VERSION 5.8 ;
BUSBITCHARS "[]" ;
DIVIDERCHAR "/" ;
UNITS
    DATABASE MICRONS 2000 ;
END UNITS

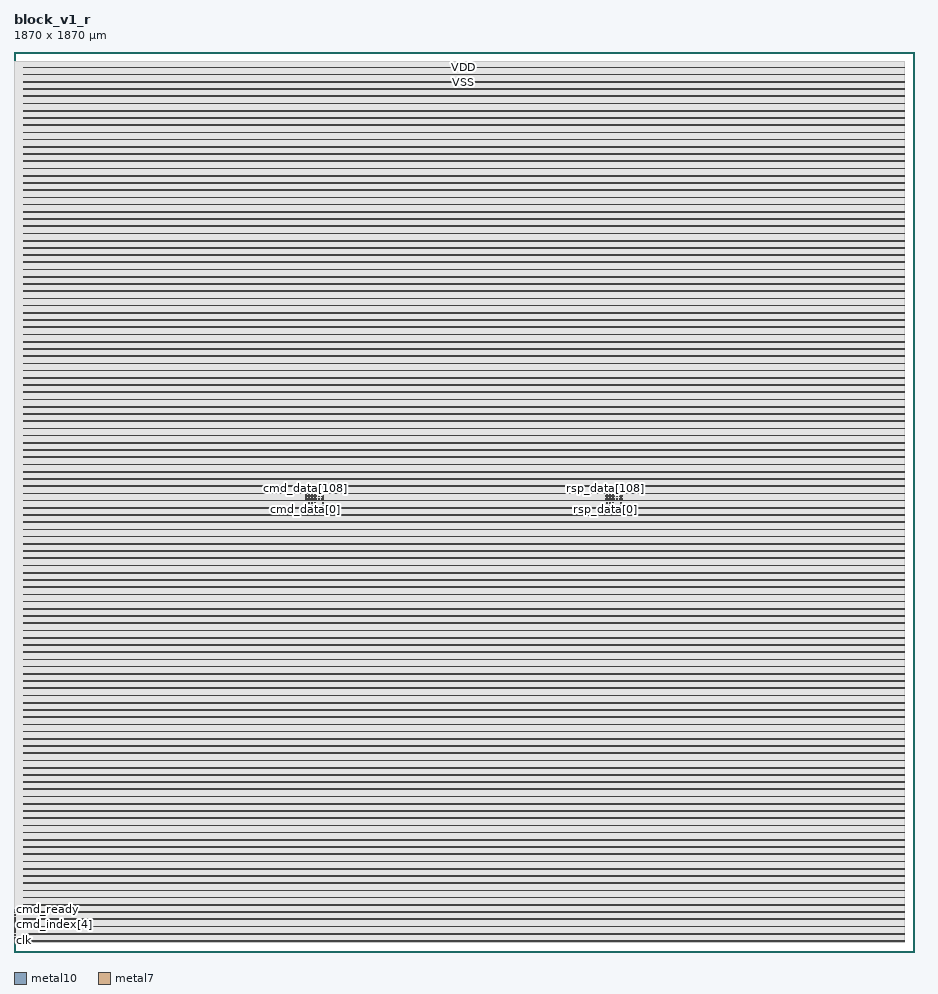
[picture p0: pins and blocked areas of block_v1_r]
MACRO block_v1_r
  FOREIGN block_v1_r 0 0 ;
  CLASS BLOCK ;
  SIZE 1870 BY 1870 ;
  PIN busy
    DIRECTION OUTPUT ;
    USE SIGNAL ;
    PORT
      LAYER metal10 ;
        RECT  1.295 20.47 2.095 21.27 ;
    END
  END busy
  PIN clk
    DIRECTION INPUT ;
    USE SIGNAL ;
    PORT
      LAYER metal10 ;
        RECT  1.295 23.67 2.095 24.47 ;
    END
  END clk
  PIN cmd_data[0]
    DIRECTION INPUT ;
    USE SIGNAL ;
    PORT
      LAYER metal10 ;
        RECT  606.095 918.07 606.895 918.87 ;
    END
  END cmd_data[0]
  PIN cmd_data[100]
    DIRECTION INPUT ;
    USE SIGNAL ;
    PORT
      LAYER metal10 ;
        RECT  618.895 943.67 619.695 944.47 ;
    END
  END cmd_data[100]
  PIN cmd_data[101]
    DIRECTION INPUT ;
    USE SIGNAL ;
    PORT
      LAYER metal10 ;
        RECT  622.095 943.67 622.895 944.47 ;
    END
  END cmd_data[101]
  PIN cmd_data[102]
    DIRECTION INPUT ;
    USE SIGNAL ;
    PORT
      LAYER metal10 ;
        RECT  625.295 943.67 626.095 944.47 ;
    END
  END cmd_data[102]
  PIN cmd_data[103]
    DIRECTION INPUT ;
    USE SIGNAL ;
    PORT
      LAYER metal10 ;
        RECT  628.495 943.67 629.295 944.47 ;
    END
  END cmd_data[103]
  PIN cmd_data[104]
    DIRECTION INPUT ;
    USE SIGNAL ;
    PORT
      LAYER metal10 ;
        RECT  631.695 943.67 632.495 944.47 ;
    END
  END cmd_data[104]
  PIN cmd_data[105]
    DIRECTION INPUT ;
    USE SIGNAL ;
    PORT
      LAYER metal10 ;
        RECT  634.895 943.67 635.695 944.47 ;
    END
  END cmd_data[105]
  PIN cmd_data[106]
    DIRECTION INPUT ;
    USE SIGNAL ;
    PORT
      LAYER metal10 ;
        RECT  638.095 943.67 638.895 944.47 ;
    END
  END cmd_data[106]
  PIN cmd_data[107]
    DIRECTION INPUT ;
    USE SIGNAL ;
    PORT
      LAYER metal10 ;
        RECT  641.295 943.67 642.095 944.47 ;
    END
  END cmd_data[107]
  PIN cmd_data[108]
    DIRECTION INPUT ;
    USE SIGNAL ;
    PORT
      LAYER metal10 ;
        RECT  606.095 946.87 606.895 947.67 ;
    END
  END cmd_data[108]
  PIN cmd_data[109]
    DIRECTION INPUT ;
    USE SIGNAL ;
    PORT
      LAYER metal10 ;
        RECT  609.295 946.87 610.095 947.67 ;
    END
  END cmd_data[109]
  PIN cmd_data[10]
    DIRECTION INPUT ;
    USE SIGNAL ;
    PORT
      LAYER metal10 ;
        RECT  638.095 918.07 638.895 918.87 ;
    END
  END cmd_data[10]
  PIN cmd_data[110]
    DIRECTION INPUT ;
    USE SIGNAL ;
    PORT
      LAYER metal10 ;
        RECT  612.495 946.87 613.295 947.67 ;
    END
  END cmd_data[110]
  PIN cmd_data[111]
    DIRECTION INPUT ;
    USE SIGNAL ;
    PORT
      LAYER metal10 ;
        RECT  615.695 946.87 616.495 947.67 ;
    END
  END cmd_data[111]
  PIN cmd_data[112]
    DIRECTION INPUT ;
    USE SIGNAL ;
    PORT
      LAYER metal10 ;
        RECT  618.895 946.87 619.695 947.67 ;
    END
  END cmd_data[112]
  PIN cmd_data[113]
    DIRECTION INPUT ;
    USE SIGNAL ;
    PORT
      LAYER metal10 ;
        RECT  622.095 946.87 622.895 947.67 ;
    END
  END cmd_data[113]
  PIN cmd_data[114]
    DIRECTION INPUT ;
    USE SIGNAL ;
    PORT
      LAYER metal10 ;
        RECT  625.295 946.87 626.095 947.67 ;
    END
  END cmd_data[114]
  PIN cmd_data[115]
    DIRECTION INPUT ;
    USE SIGNAL ;
    PORT
      LAYER metal10 ;
        RECT  628.495 946.87 629.295 947.67 ;
    END
  END cmd_data[115]
  PIN cmd_data[116]
    DIRECTION INPUT ;
    USE SIGNAL ;
    PORT
      LAYER metal10 ;
        RECT  631.695 946.87 632.495 947.67 ;
    END
  END cmd_data[116]
  PIN cmd_data[117]
    DIRECTION INPUT ;
    USE SIGNAL ;
    PORT
      LAYER metal10 ;
        RECT  634.895 946.87 635.695 947.67 ;
    END
  END cmd_data[117]
  PIN cmd_data[118]
    DIRECTION INPUT ;
    USE SIGNAL ;
    PORT
      LAYER metal10 ;
        RECT  638.095 946.87 638.895 947.67 ;
    END
  END cmd_data[118]
  PIN cmd_data[119]
    DIRECTION INPUT ;
    USE SIGNAL ;
    PORT
      LAYER metal10 ;
        RECT  641.295 946.87 642.095 947.67 ;
    END
  END cmd_data[119]
  PIN cmd_data[11]
    DIRECTION INPUT ;
    USE SIGNAL ;
    PORT
      LAYER metal10 ;
        RECT  641.295 918.07 642.095 918.87 ;
    END
  END cmd_data[11]
  PIN cmd_data[120]
    DIRECTION INPUT ;
    USE SIGNAL ;
    PORT
      LAYER metal10 ;
        RECT  606.095 950.07 606.895 950.87 ;
    END
  END cmd_data[120]
  PIN cmd_data[121]
    DIRECTION INPUT ;
    USE SIGNAL ;
    PORT
      LAYER metal10 ;
        RECT  609.295 950.07 610.095 950.87 ;
    END
  END cmd_data[121]
  PIN cmd_data[122]
    DIRECTION INPUT ;
    USE SIGNAL ;
    PORT
      LAYER metal10 ;
        RECT  612.495 950.07 613.295 950.87 ;
    END
  END cmd_data[122]
  PIN cmd_data[123]
    DIRECTION INPUT ;
    USE SIGNAL ;
    PORT
      LAYER metal10 ;
        RECT  615.695 950.07 616.495 950.87 ;
    END
  END cmd_data[123]
  PIN cmd_data[124]
    DIRECTION INPUT ;
    USE SIGNAL ;
    PORT
      LAYER metal10 ;
        RECT  618.895 950.07 619.695 950.87 ;
    END
  END cmd_data[124]
  PIN cmd_data[125]
    DIRECTION INPUT ;
    USE SIGNAL ;
    PORT
      LAYER metal10 ;
        RECT  622.095 950.07 622.895 950.87 ;
    END
  END cmd_data[125]
  PIN cmd_data[126]
    DIRECTION INPUT ;
    USE SIGNAL ;
    PORT
      LAYER metal10 ;
        RECT  625.295 950.07 626.095 950.87 ;
    END
  END cmd_data[126]
  PIN cmd_data[127]
    DIRECTION INPUT ;
    USE SIGNAL ;
    PORT
      LAYER metal10 ;
        RECT  628.495 950.07 629.295 950.87 ;
    END
  END cmd_data[127]
  PIN cmd_data[12]
    DIRECTION INPUT ;
    USE SIGNAL ;
    PORT
      LAYER metal10 ;
        RECT  606.095 921.27 606.895 922.07 ;
    END
  END cmd_data[12]
  PIN cmd_data[13]
    DIRECTION INPUT ;
    USE SIGNAL ;
    PORT
      LAYER metal10 ;
        RECT  609.295 921.27 610.095 922.07 ;
    END
  END cmd_data[13]
  PIN cmd_data[14]
    DIRECTION INPUT ;
    USE SIGNAL ;
    PORT
      LAYER metal10 ;
        RECT  612.495 921.27 613.295 922.07 ;
    END
  END cmd_data[14]
  PIN cmd_data[15]
    DIRECTION INPUT ;
    USE SIGNAL ;
    PORT
      LAYER metal10 ;
        RECT  615.695 921.27 616.495 922.07 ;
    END
  END cmd_data[15]
  PIN cmd_data[16]
    DIRECTION INPUT ;
    USE SIGNAL ;
    PORT
      LAYER metal10 ;
        RECT  618.895 921.27 619.695 922.07 ;
    END
  END cmd_data[16]
  PIN cmd_data[17]
    DIRECTION INPUT ;
    USE SIGNAL ;
    PORT
      LAYER metal10 ;
        RECT  622.095 921.27 622.895 922.07 ;
    END
  END cmd_data[17]
  PIN cmd_data[18]
    DIRECTION INPUT ;
    USE SIGNAL ;
    PORT
      LAYER metal10 ;
        RECT  625.295 921.27 626.095 922.07 ;
    END
  END cmd_data[18]
  PIN cmd_data[19]
    DIRECTION INPUT ;
    USE SIGNAL ;
    PORT
      LAYER metal10 ;
        RECT  628.495 921.27 629.295 922.07 ;
    END
  END cmd_data[19]
  PIN cmd_data[1]
    DIRECTION INPUT ;
    USE SIGNAL ;
    PORT
      LAYER metal10 ;
        RECT  609.295 918.07 610.095 918.87 ;
    END
  END cmd_data[1]
  PIN cmd_data[20]
    DIRECTION INPUT ;
    USE SIGNAL ;
    PORT
      LAYER metal10 ;
        RECT  631.695 921.27 632.495 922.07 ;
    END
  END cmd_data[20]
  PIN cmd_data[21]
    DIRECTION INPUT ;
    USE SIGNAL ;
    PORT
      LAYER metal10 ;
        RECT  634.895 921.27 635.695 922.07 ;
    END
  END cmd_data[21]
  PIN cmd_data[22]
    DIRECTION INPUT ;
    USE SIGNAL ;
    PORT
      LAYER metal10 ;
        RECT  638.095 921.27 638.895 922.07 ;
    END
  END cmd_data[22]
  PIN cmd_data[23]
    DIRECTION INPUT ;
    USE SIGNAL ;
    PORT
      LAYER metal10 ;
        RECT  641.295 921.27 642.095 922.07 ;
    END
  END cmd_data[23]
  PIN cmd_data[24]
    DIRECTION INPUT ;
    USE SIGNAL ;
    PORT
      LAYER metal10 ;
        RECT  606.095 924.47 606.895 925.27 ;
    END
  END cmd_data[24]
  PIN cmd_data[25]
    DIRECTION INPUT ;
    USE SIGNAL ;
    PORT
      LAYER metal10 ;
        RECT  609.295 924.47 610.095 925.27 ;
    END
  END cmd_data[25]
  PIN cmd_data[26]
    DIRECTION INPUT ;
    USE SIGNAL ;
    PORT
      LAYER metal10 ;
        RECT  612.495 924.47 613.295 925.27 ;
    END
  END cmd_data[26]
  PIN cmd_data[27]
    DIRECTION INPUT ;
    USE SIGNAL ;
    PORT
      LAYER metal10 ;
        RECT  615.695 924.47 616.495 925.27 ;
    END
  END cmd_data[27]
  PIN cmd_data[28]
    DIRECTION INPUT ;
    USE SIGNAL ;
    PORT
      LAYER metal10 ;
        RECT  618.895 924.47 619.695 925.27 ;
    END
  END cmd_data[28]
  PIN cmd_data[29]
    DIRECTION INPUT ;
    USE SIGNAL ;
    PORT
      LAYER metal10 ;
        RECT  622.095 924.47 622.895 925.27 ;
    END
  END cmd_data[29]
  PIN cmd_data[2]
    DIRECTION INPUT ;
    USE SIGNAL ;
    PORT
      LAYER metal10 ;
        RECT  612.495 918.07 613.295 918.87 ;
    END
  END cmd_data[2]
  PIN cmd_data[30]
    DIRECTION INPUT ;
    USE SIGNAL ;
    PORT
      LAYER metal10 ;
        RECT  625.295 924.47 626.095 925.27 ;
    END
  END cmd_data[30]
  PIN cmd_data[31]
    DIRECTION INPUT ;
    USE SIGNAL ;
    PORT
      LAYER metal10 ;
        RECT  628.495 924.47 629.295 925.27 ;
    END
  END cmd_data[31]
  PIN cmd_data[32]
    DIRECTION INPUT ;
    USE SIGNAL ;
    PORT
      LAYER metal10 ;
        RECT  631.695 924.47 632.495 925.27 ;
    END
  END cmd_data[32]
  PIN cmd_data[33]
    DIRECTION INPUT ;
    USE SIGNAL ;
    PORT
      LAYER metal10 ;
        RECT  634.895 924.47 635.695 925.27 ;
    END
  END cmd_data[33]
  PIN cmd_data[34]
    DIRECTION INPUT ;
    USE SIGNAL ;
    PORT
      LAYER metal10 ;
        RECT  638.095 924.47 638.895 925.27 ;
    END
  END cmd_data[34]
  PIN cmd_data[35]
    DIRECTION INPUT ;
    USE SIGNAL ;
    PORT
      LAYER metal10 ;
        RECT  641.295 924.47 642.095 925.27 ;
    END
  END cmd_data[35]
  PIN cmd_data[36]
    DIRECTION INPUT ;
    USE SIGNAL ;
    PORT
      LAYER metal10 ;
        RECT  606.095 927.67 606.895 928.47 ;
    END
  END cmd_data[36]
  PIN cmd_data[37]
    DIRECTION INPUT ;
    USE SIGNAL ;
    PORT
      LAYER metal10 ;
        RECT  609.295 927.67 610.095 928.47 ;
    END
  END cmd_data[37]
  PIN cmd_data[38]
    DIRECTION INPUT ;
    USE SIGNAL ;
    PORT
      LAYER metal10 ;
        RECT  612.495 927.67 613.295 928.47 ;
    END
  END cmd_data[38]
  PIN cmd_data[39]
    DIRECTION INPUT ;
    USE SIGNAL ;
    PORT
      LAYER metal10 ;
        RECT  615.695 927.67 616.495 928.47 ;
    END
  END cmd_data[39]
  PIN cmd_data[3]
    DIRECTION INPUT ;
    USE SIGNAL ;
    PORT
      LAYER metal10 ;
        RECT  615.695 918.07 616.495 918.87 ;
    END
  END cmd_data[3]
  PIN cmd_data[40]
    DIRECTION INPUT ;
    USE SIGNAL ;
    PORT
      LAYER metal10 ;
        RECT  618.895 927.67 619.695 928.47 ;
    END
  END cmd_data[40]
  PIN cmd_data[41]
    DIRECTION INPUT ;
    USE SIGNAL ;
    PORT
      LAYER metal10 ;
        RECT  622.095 927.67 622.895 928.47 ;
    END
  END cmd_data[41]
  PIN cmd_data[42]
    DIRECTION INPUT ;
    USE SIGNAL ;
    PORT
      LAYER metal10 ;
        RECT  625.295 927.67 626.095 928.47 ;
    END
  END cmd_data[42]
  PIN cmd_data[43]
    DIRECTION INPUT ;
    USE SIGNAL ;
    PORT
      LAYER metal10 ;
        RECT  628.495 927.67 629.295 928.47 ;
    END
  END cmd_data[43]
  PIN cmd_data[44]
    DIRECTION INPUT ;
    USE SIGNAL ;
    PORT
      LAYER metal10 ;
        RECT  631.695 927.67 632.495 928.47 ;
    END
  END cmd_data[44]
  PIN cmd_data[45]
    DIRECTION INPUT ;
    USE SIGNAL ;
    PORT
      LAYER metal10 ;
        RECT  634.895 927.67 635.695 928.47 ;
    END
  END cmd_data[45]
  PIN cmd_data[46]
    DIRECTION INPUT ;
    USE SIGNAL ;
    PORT
      LAYER metal10 ;
        RECT  638.095 927.67 638.895 928.47 ;
    END
  END cmd_data[46]
  PIN cmd_data[47]
    DIRECTION INPUT ;
    USE SIGNAL ;
    PORT
      LAYER metal10 ;
        RECT  641.295 927.67 642.095 928.47 ;
    END
  END cmd_data[47]
  PIN cmd_data[48]
    DIRECTION INPUT ;
    USE SIGNAL ;
    PORT
      LAYER metal10 ;
        RECT  606.095 930.87 606.895 931.67 ;
    END
  END cmd_data[48]
  PIN cmd_data[49]
    DIRECTION INPUT ;
    USE SIGNAL ;
    PORT
      LAYER metal10 ;
        RECT  609.295 930.87 610.095 931.67 ;
    END
  END cmd_data[49]
  PIN cmd_data[4]
    DIRECTION INPUT ;
    USE SIGNAL ;
    PORT
      LAYER metal10 ;
        RECT  618.895 918.07 619.695 918.87 ;
    END
  END cmd_data[4]
  PIN cmd_data[50]
    DIRECTION INPUT ;
    USE SIGNAL ;
    PORT
      LAYER metal10 ;
        RECT  612.495 930.87 613.295 931.67 ;
    END
  END cmd_data[50]
  PIN cmd_data[51]
    DIRECTION INPUT ;
    USE SIGNAL ;
    PORT
      LAYER metal10 ;
        RECT  615.695 930.87 616.495 931.67 ;
    END
  END cmd_data[51]
  PIN cmd_data[52]
    DIRECTION INPUT ;
    USE SIGNAL ;
    PORT
      LAYER metal10 ;
        RECT  618.895 930.87 619.695 931.67 ;
    END
  END cmd_data[52]
  PIN cmd_data[53]
    DIRECTION INPUT ;
    USE SIGNAL ;
    PORT
      LAYER metal10 ;
        RECT  622.095 930.87 622.895 931.67 ;
    END
  END cmd_data[53]
  PIN cmd_data[54]
    DIRECTION INPUT ;
    USE SIGNAL ;
    PORT
      LAYER metal10 ;
        RECT  625.295 930.87 626.095 931.67 ;
    END
  END cmd_data[54]
  PIN cmd_data[55]
    DIRECTION INPUT ;
    USE SIGNAL ;
    PORT
      LAYER metal10 ;
        RECT  628.495 930.87 629.295 931.67 ;
    END
  END cmd_data[55]
  PIN cmd_data[56]
    DIRECTION INPUT ;
    USE SIGNAL ;
    PORT
      LAYER metal10 ;
        RECT  631.695 930.87 632.495 931.67 ;
    END
  END cmd_data[56]
  PIN cmd_data[57]
    DIRECTION INPUT ;
    USE SIGNAL ;
    PORT
      LAYER metal10 ;
        RECT  634.895 930.87 635.695 931.67 ;
    END
  END cmd_data[57]
  PIN cmd_data[58]
    DIRECTION INPUT ;
    USE SIGNAL ;
    PORT
      LAYER metal10 ;
        RECT  638.095 930.87 638.895 931.67 ;
    END
  END cmd_data[58]
  PIN cmd_data[59]
    DIRECTION INPUT ;
    USE SIGNAL ;
    PORT
      LAYER metal10 ;
        RECT  641.295 930.87 642.095 931.67 ;
    END
  END cmd_data[59]
  PIN cmd_data[5]
    DIRECTION INPUT ;
    USE SIGNAL ;
    PORT
      LAYER metal10 ;
        RECT  622.095 918.07 622.895 918.87 ;
    END
  END cmd_data[5]
  PIN cmd_data[60]
    DIRECTION INPUT ;
    USE SIGNAL ;
    PORT
      LAYER metal10 ;
        RECT  606.095 934.07 606.895 934.87 ;
    END
  END cmd_data[60]
  PIN cmd_data[61]
    DIRECTION INPUT ;
    USE SIGNAL ;
    PORT
      LAYER metal10 ;
        RECT  609.295 934.07 610.095 934.87 ;
    END
  END cmd_data[61]
  PIN cmd_data[62]
    DIRECTION INPUT ;
    USE SIGNAL ;
    PORT
      LAYER metal10 ;
        RECT  612.495 934.07 613.295 934.87 ;
    END
  END cmd_data[62]
  PIN cmd_data[63]
    DIRECTION INPUT ;
    USE SIGNAL ;
    PORT
      LAYER metal10 ;
        RECT  615.695 934.07 616.495 934.87 ;
    END
  END cmd_data[63]
  PIN cmd_data[64]
    DIRECTION INPUT ;
    USE SIGNAL ;
    PORT
      LAYER metal10 ;
        RECT  618.895 934.07 619.695 934.87 ;
    END
  END cmd_data[64]
  PIN cmd_data[65]
    DIRECTION INPUT ;
    USE SIGNAL ;
    PORT
      LAYER metal10 ;
        RECT  622.095 934.07 622.895 934.87 ;
    END
  END cmd_data[65]
  PIN cmd_data[66]
    DIRECTION INPUT ;
    USE SIGNAL ;
    PORT
      LAYER metal10 ;
        RECT  625.295 934.07 626.095 934.87 ;
    END
  END cmd_data[66]
  PIN cmd_data[67]
    DIRECTION INPUT ;
    USE SIGNAL ;
    PORT
      LAYER metal10 ;
        RECT  628.495 934.07 629.295 934.87 ;
    END
  END cmd_data[67]
  PIN cmd_data[68]
    DIRECTION INPUT ;
    USE SIGNAL ;
    PORT
      LAYER metal10 ;
        RECT  631.695 934.07 632.495 934.87 ;
    END
  END cmd_data[68]
  PIN cmd_data[69]
    DIRECTION INPUT ;
    USE SIGNAL ;
    PORT
      LAYER metal10 ;
        RECT  634.895 934.07 635.695 934.87 ;
    END
  END cmd_data[69]
  PIN cmd_data[6]
    DIRECTION INPUT ;
    USE SIGNAL ;
    PORT
      LAYER metal10 ;
        RECT  625.295 918.07 626.095 918.87 ;
    END
  END cmd_data[6]
  PIN cmd_data[70]
    DIRECTION INPUT ;
    USE SIGNAL ;
    PORT
      LAYER metal10 ;
        RECT  638.095 934.07 638.895 934.87 ;
    END
  END cmd_data[70]
  PIN cmd_data[71]
    DIRECTION INPUT ;
    USE SIGNAL ;
    PORT
      LAYER metal10 ;
        RECT  641.295 934.07 642.095 934.87 ;
    END
  END cmd_data[71]
  PIN cmd_data[72]
    DIRECTION INPUT ;
    USE SIGNAL ;
    PORT
      LAYER metal10 ;
        RECT  606.095 937.27 606.895 938.07 ;
    END
  END cmd_data[72]
  PIN cmd_data[73]
    DIRECTION INPUT ;
    USE SIGNAL ;
    PORT
      LAYER metal10 ;
        RECT  609.295 937.27 610.095 938.07 ;
    END
  END cmd_data[73]
  PIN cmd_data[74]
    DIRECTION INPUT ;
    USE SIGNAL ;
    PORT
      LAYER metal10 ;
        RECT  612.495 937.27 613.295 938.07 ;
    END
  END cmd_data[74]
  PIN cmd_data[75]
    DIRECTION INPUT ;
    USE SIGNAL ;
    PORT
      LAYER metal10 ;
        RECT  615.695 937.27 616.495 938.07 ;
    END
  END cmd_data[75]
  PIN cmd_data[76]
    DIRECTION INPUT ;
    USE SIGNAL ;
    PORT
      LAYER metal10 ;
        RECT  618.895 937.27 619.695 938.07 ;
    END
  END cmd_data[76]
  PIN cmd_data[77]
    DIRECTION INPUT ;
    USE SIGNAL ;
    PORT
      LAYER metal10 ;
        RECT  622.095 937.27 622.895 938.07 ;
    END
  END cmd_data[77]
  PIN cmd_data[78]
    DIRECTION INPUT ;
    USE SIGNAL ;
    PORT
      LAYER metal10 ;
        RECT  625.295 937.27 626.095 938.07 ;
    END
  END cmd_data[78]
  PIN cmd_data[79]
    DIRECTION INPUT ;
    USE SIGNAL ;
    PORT
      LAYER metal10 ;
        RECT  628.495 937.27 629.295 938.07 ;
    END
  END cmd_data[79]
  PIN cmd_data[7]
    DIRECTION INPUT ;
    USE SIGNAL ;
    PORT
      LAYER metal10 ;
        RECT  628.495 918.07 629.295 918.87 ;
    END
  END cmd_data[7]
  PIN cmd_data[80]
    DIRECTION INPUT ;
    USE SIGNAL ;
    PORT
      LAYER metal10 ;
        RECT  631.695 937.27 632.495 938.07 ;
    END
  END cmd_data[80]
  PIN cmd_data[81]
    DIRECTION INPUT ;
    USE SIGNAL ;
    PORT
      LAYER metal10 ;
        RECT  634.895 937.27 635.695 938.07 ;
    END
  END cmd_data[81]
  PIN cmd_data[82]
    DIRECTION INPUT ;
    USE SIGNAL ;
    PORT
      LAYER metal10 ;
        RECT  638.095 937.27 638.895 938.07 ;
    END
  END cmd_data[82]
  PIN cmd_data[83]
    DIRECTION INPUT ;
    USE SIGNAL ;
    PORT
      LAYER metal10 ;
        RECT  641.295 937.27 642.095 938.07 ;
    END
  END cmd_data[83]
  PIN cmd_data[84]
    DIRECTION INPUT ;
    USE SIGNAL ;
    PORT
      LAYER metal10 ;
        RECT  606.095 940.47 606.895 941.27 ;
    END
  END cmd_data[84]
  PIN cmd_data[85]
    DIRECTION INPUT ;
    USE SIGNAL ;
    PORT
      LAYER metal10 ;
        RECT  609.295 940.47 610.095 941.27 ;
    END
  END cmd_data[85]
  PIN cmd_data[86]
    DIRECTION INPUT ;
    USE SIGNAL ;
    PORT
      LAYER metal10 ;
        RECT  612.495 940.47 613.295 941.27 ;
    END
  END cmd_data[86]
  PIN cmd_data[87]
    DIRECTION INPUT ;
    USE SIGNAL ;
    PORT
      LAYER metal10 ;
        RECT  615.695 940.47 616.495 941.27 ;
    END
  END cmd_data[87]
  PIN cmd_data[88]
    DIRECTION INPUT ;
    USE SIGNAL ;
    PORT
      LAYER metal10 ;
        RECT  618.895 940.47 619.695 941.27 ;
    END
  END cmd_data[88]
  PIN cmd_data[89]
    DIRECTION INPUT ;
    USE SIGNAL ;
    PORT
      LAYER metal10 ;
        RECT  622.095 940.47 622.895 941.27 ;
    END
  END cmd_data[89]
  PIN cmd_data[8]
    DIRECTION INPUT ;
    USE SIGNAL ;
    PORT
      LAYER metal10 ;
        RECT  631.695 918.07 632.495 918.87 ;
    END
  END cmd_data[8]
  PIN cmd_data[90]
    DIRECTION INPUT ;
    USE SIGNAL ;
    PORT
      LAYER metal10 ;
        RECT  625.295 940.47 626.095 941.27 ;
    END
  END cmd_data[90]
  PIN cmd_data[91]
    DIRECTION INPUT ;
    USE SIGNAL ;
    PORT
      LAYER metal10 ;
        RECT  628.495 940.47 629.295 941.27 ;
    END
  END cmd_data[91]
  PIN cmd_data[92]
    DIRECTION INPUT ;
    USE SIGNAL ;
    PORT
      LAYER metal10 ;
        RECT  631.695 940.47 632.495 941.27 ;
    END
  END cmd_data[92]
  PIN cmd_data[93]
    DIRECTION INPUT ;
    USE SIGNAL ;
    PORT
      LAYER metal10 ;
        RECT  634.895 940.47 635.695 941.27 ;
    END
  END cmd_data[93]
  PIN cmd_data[94]
    DIRECTION INPUT ;
    USE SIGNAL ;
    PORT
      LAYER metal10 ;
        RECT  638.095 940.47 638.895 941.27 ;
    END
  END cmd_data[94]
  PIN cmd_data[95]
    DIRECTION INPUT ;
    USE SIGNAL ;
    PORT
      LAYER metal10 ;
        RECT  641.295 940.47 642.095 941.27 ;
    END
  END cmd_data[95]
  PIN cmd_data[96]
    DIRECTION INPUT ;
    USE SIGNAL ;
    PORT
      LAYER metal10 ;
        RECT  606.095 943.67 606.895 944.47 ;
    END
  END cmd_data[96]
  PIN cmd_data[97]
    DIRECTION INPUT ;
    USE SIGNAL ;
    PORT
      LAYER metal10 ;
        RECT  609.295 943.67 610.095 944.47 ;
    END
  END cmd_data[97]
  PIN cmd_data[98]
    DIRECTION INPUT ;
    USE SIGNAL ;
    PORT
      LAYER metal10 ;
        RECT  612.495 943.67 613.295 944.47 ;
    END
  END cmd_data[98]
  PIN cmd_data[99]
    DIRECTION INPUT ;
    USE SIGNAL ;
    PORT
      LAYER metal10 ;
        RECT  615.695 943.67 616.495 944.47 ;
    END
  END cmd_data[99]
  PIN cmd_data[9]
    DIRECTION INPUT ;
    USE SIGNAL ;
    PORT
      LAYER metal10 ;
        RECT  634.895 918.07 635.695 918.87 ;
    END
  END cmd_data[9]
  PIN cmd_index[0]
    DIRECTION INPUT ;
    USE SIGNAL ;
    PORT
      LAYER metal10 ;
        RECT  1.295 26.87 2.095 27.67 ;
    END
  END cmd_index[0]
  PIN cmd_index[1]
    DIRECTION INPUT ;
    USE SIGNAL ;
    PORT
      LAYER metal10 ;
        RECT  1.295 30.07 2.095 30.87 ;
    END
  END cmd_index[1]
  PIN cmd_index[2]
    DIRECTION INPUT ;
    USE SIGNAL ;
    PORT
      LAYER metal10 ;
        RECT  1.295 33.27 2.095 34.07 ;
    END
  END cmd_index[2]
  PIN cmd_index[3]
    DIRECTION INPUT ;
    USE SIGNAL ;
    PORT
      LAYER metal10 ;
        RECT  1.295 36.47 2.095 37.27 ;
    END
  END cmd_index[3]
  PIN cmd_index[4]
    DIRECTION INPUT ;
    USE SIGNAL ;
    PORT
      LAYER metal10 ;
        RECT  1.295 39.67 2.095 40.47 ;
    END
  END cmd_index[4]
  PIN cmd_index[5]
    DIRECTION INPUT ;
    USE SIGNAL ;
    PORT
      LAYER metal10 ;
        RECT  1.295 42.87 2.095 43.67 ;
    END
  END cmd_index[5]
  PIN cmd_index[6]
    DIRECTION INPUT ;
    USE SIGNAL ;
    PORT
      LAYER metal10 ;
        RECT  1.295 46.07 2.095 46.87 ;
    END
  END cmd_index[6]
  PIN cmd_index[7]
    DIRECTION INPUT ;
    USE SIGNAL ;
    PORT
      LAYER metal10 ;
        RECT  1.295 49.27 2.095 50.07 ;
    END
  END cmd_index[7]
  PIN cmd_index[8]
    DIRECTION INPUT ;
    USE SIGNAL ;
    PORT
      LAYER metal10 ;
        RECT  1.295 52.47 2.095 53.27 ;
    END
  END cmd_index[8]
  PIN cmd_index[9]
    DIRECTION INPUT ;
    USE SIGNAL ;
    PORT
      LAYER metal10 ;
        RECT  1.295 55.67 2.095 56.47 ;
    END
  END cmd_index[9]
  PIN cmd_op[0]
    DIRECTION INPUT ;
    USE SIGNAL ;
    PORT
      LAYER metal10 ;
        RECT  1.295 58.87 2.095 59.67 ;
    END
  END cmd_op[0]
  PIN cmd_op[1]
    DIRECTION INPUT ;
    USE SIGNAL ;
    PORT
      LAYER metal10 ;
        RECT  1.295 62.07 2.095 62.87 ;
    END
  END cmd_op[1]
  PIN cmd_op[2]
    DIRECTION INPUT ;
    USE SIGNAL ;
    PORT
      LAYER metal10 ;
        RECT  1.295 65.27 2.095 66.07 ;
    END
  END cmd_op[2]
  PIN cmd_op[3]
    DIRECTION INPUT ;
    USE SIGNAL ;
    PORT
      LAYER metal10 ;
        RECT  1.295 68.47 2.095 69.27 ;
    END
  END cmd_op[3]
  PIN cmd_ready
    DIRECTION OUTPUT ;
    USE SIGNAL ;
    PORT
      LAYER metal10 ;
        RECT  1.295 71.67 2.095 72.47 ;
    END
  END cmd_ready
  PIN cmd_valid
    DIRECTION INPUT ;
    USE SIGNAL ;
    PORT
      LAYER metal10 ;
        RECT  1.295 74.87 2.095 75.67 ;
    END
  END cmd_valid
  PIN reset
    DIRECTION INPUT ;
    USE SIGNAL ;
    PORT
      LAYER metal10 ;
        RECT  1.295 78.07 2.095 78.87 ;
    END
  END reset
  PIN rsp_data[0]
    DIRECTION OUTPUT ;
    USE SIGNAL ;
    PORT
      LAYER metal10 ;
        RECT  1228.49 918.07 1229.29 918.87 ;
    END
  END rsp_data[0]
  PIN rsp_data[100]
    DIRECTION OUTPUT ;
    USE SIGNAL ;
    PORT
      LAYER metal10 ;
        RECT  1241.29 943.67 1242.09 944.47 ;
    END
  END rsp_data[100]
  PIN rsp_data[101]
    DIRECTION OUTPUT ;
    USE SIGNAL ;
    PORT
      LAYER metal10 ;
        RECT  1244.49 943.67 1245.29 944.47 ;
    END
  END rsp_data[101]
  PIN rsp_data[102]
    DIRECTION OUTPUT ;
    USE SIGNAL ;
    PORT
      LAYER metal10 ;
        RECT  1247.7 943.67 1248.5 944.47 ;
    END
  END rsp_data[102]
  PIN rsp_data[103]
    DIRECTION OUTPUT ;
    USE SIGNAL ;
    PORT
      LAYER metal10 ;
        RECT  1250.9 943.67 1251.7 944.47 ;
    END
  END rsp_data[103]
  PIN rsp_data[104]
    DIRECTION OUTPUT ;
    USE SIGNAL ;
    PORT
      LAYER metal10 ;
        RECT  1254.09 943.67 1254.89 944.47 ;
    END
  END rsp_data[104]
  PIN rsp_data[105]
    DIRECTION OUTPUT ;
    USE SIGNAL ;
    PORT
      LAYER metal10 ;
        RECT  1257.29 943.67 1258.09 944.47 ;
    END
  END rsp_data[105]
  PIN rsp_data[106]
    DIRECTION OUTPUT ;
    USE SIGNAL ;
    PORT
      LAYER metal10 ;
        RECT  1260.49 943.67 1261.29 944.47 ;
    END
  END rsp_data[106]
  PIN rsp_data[107]
    DIRECTION OUTPUT ;
    USE SIGNAL ;
    PORT
      LAYER metal10 ;
        RECT  1263.7 943.67 1264.5 944.47 ;
    END
  END rsp_data[107]
  PIN rsp_data[108]
    DIRECTION OUTPUT ;
    USE SIGNAL ;
    PORT
      LAYER metal10 ;
        RECT  1228.49 946.87 1229.29 947.67 ;
    END
  END rsp_data[108]
  PIN rsp_data[109]
    DIRECTION OUTPUT ;
    USE SIGNAL ;
    PORT
      LAYER metal10 ;
        RECT  1231.7 946.87 1232.5 947.67 ;
    END
  END rsp_data[109]
  PIN rsp_data[10]
    DIRECTION OUTPUT ;
    USE SIGNAL ;
    PORT
      LAYER metal10 ;
        RECT  1260.49 918.07 1261.29 918.87 ;
    END
  END rsp_data[10]
  PIN rsp_data[110]
    DIRECTION OUTPUT ;
    USE SIGNAL ;
    PORT
      LAYER metal10 ;
        RECT  1234.9 946.87 1235.7 947.67 ;
    END
  END rsp_data[110]
  PIN rsp_data[111]
    DIRECTION OUTPUT ;
    USE SIGNAL ;
    PORT
      LAYER metal10 ;
        RECT  1238.09 946.87 1238.89 947.67 ;
    END
  END rsp_data[111]
  PIN rsp_data[112]
    DIRECTION OUTPUT ;
    USE SIGNAL ;
    PORT
      LAYER metal10 ;
        RECT  1241.29 946.87 1242.09 947.67 ;
    END
  END rsp_data[112]
  PIN rsp_data[113]
    DIRECTION OUTPUT ;
    USE SIGNAL ;
    PORT
      LAYER metal10 ;
        RECT  1244.49 946.87 1245.29 947.67 ;
    END
  END rsp_data[113]
  PIN rsp_data[114]
    DIRECTION OUTPUT ;
    USE SIGNAL ;
    PORT
      LAYER metal10 ;
        RECT  1247.7 946.87 1248.5 947.67 ;
    END
  END rsp_data[114]
  PIN rsp_data[115]
    DIRECTION OUTPUT ;
    USE SIGNAL ;
    PORT
      LAYER metal10 ;
        RECT  1250.9 946.87 1251.7 947.67 ;
    END
  END rsp_data[115]
  PIN rsp_data[116]
    DIRECTION OUTPUT ;
    USE SIGNAL ;
    PORT
      LAYER metal10 ;
        RECT  1254.09 946.87 1254.89 947.67 ;
    END
  END rsp_data[116]
  PIN rsp_data[117]
    DIRECTION OUTPUT ;
    USE SIGNAL ;
    PORT
      LAYER metal10 ;
        RECT  1257.29 946.87 1258.09 947.67 ;
    END
  END rsp_data[117]
  PIN rsp_data[118]
    DIRECTION OUTPUT ;
    USE SIGNAL ;
    PORT
      LAYER metal10 ;
        RECT  1260.49 946.87 1261.29 947.67 ;
    END
  END rsp_data[118]
  PIN rsp_data[119]
    DIRECTION OUTPUT ;
    USE SIGNAL ;
    PORT
      LAYER metal10 ;
        RECT  1263.7 946.87 1264.5 947.67 ;
    END
  END rsp_data[119]
  PIN rsp_data[11]
    DIRECTION OUTPUT ;
    USE SIGNAL ;
    PORT
      LAYER metal10 ;
        RECT  1263.7 918.07 1264.5 918.87 ;
    END
  END rsp_data[11]
  PIN rsp_data[120]
    DIRECTION OUTPUT ;
    USE SIGNAL ;
    PORT
      LAYER metal10 ;
        RECT  1228.49 950.07 1229.29 950.87 ;
    END
  END rsp_data[120]
  PIN rsp_data[121]
    DIRECTION OUTPUT ;
    USE SIGNAL ;
    PORT
      LAYER metal10 ;
        RECT  1231.7 950.07 1232.5 950.87 ;
    END
  END rsp_data[121]
  PIN rsp_data[122]
    DIRECTION OUTPUT ;
    USE SIGNAL ;
    PORT
      LAYER metal10 ;
        RECT  1234.9 950.07 1235.7 950.87 ;
    END
  END rsp_data[122]
  PIN rsp_data[123]
    DIRECTION OUTPUT ;
    USE SIGNAL ;
    PORT
      LAYER metal10 ;
        RECT  1238.09 950.07 1238.89 950.87 ;
    END
  END rsp_data[123]
  PIN rsp_data[124]
    DIRECTION OUTPUT ;
    USE SIGNAL ;
    PORT
      LAYER metal10 ;
        RECT  1241.29 950.07 1242.09 950.87 ;
    END
  END rsp_data[124]
  PIN rsp_data[125]
    DIRECTION OUTPUT ;
    USE SIGNAL ;
    PORT
      LAYER metal10 ;
        RECT  1244.49 950.07 1245.29 950.87 ;
    END
  END rsp_data[125]
  PIN rsp_data[126]
    DIRECTION OUTPUT ;
    USE SIGNAL ;
    PORT
      LAYER metal10 ;
        RECT  1247.7 950.07 1248.5 950.87 ;
    END
  END rsp_data[126]
  PIN rsp_data[127]
    DIRECTION OUTPUT ;
    USE SIGNAL ;
    PORT
      LAYER metal10 ;
        RECT  1250.9 950.07 1251.7 950.87 ;
    END
  END rsp_data[127]
  PIN rsp_data[12]
    DIRECTION OUTPUT ;
    USE SIGNAL ;
    PORT
      LAYER metal10 ;
        RECT  1228.49 921.27 1229.29 922.07 ;
    END
  END rsp_data[12]
  PIN rsp_data[13]
    DIRECTION OUTPUT ;
    USE SIGNAL ;
    PORT
      LAYER metal10 ;
        RECT  1231.7 921.27 1232.5 922.07 ;
    END
  END rsp_data[13]
  PIN rsp_data[14]
    DIRECTION OUTPUT ;
    USE SIGNAL ;
    PORT
      LAYER metal10 ;
        RECT  1234.9 921.27 1235.7 922.07 ;
    END
  END rsp_data[14]
  PIN rsp_data[15]
    DIRECTION OUTPUT ;
    USE SIGNAL ;
    PORT
      LAYER metal10 ;
        RECT  1238.09 921.27 1238.89 922.07 ;
    END
  END rsp_data[15]
  PIN rsp_data[16]
    DIRECTION OUTPUT ;
    USE SIGNAL ;
    PORT
      LAYER metal10 ;
        RECT  1241.29 921.27 1242.09 922.07 ;
    END
  END rsp_data[16]
  PIN rsp_data[17]
    DIRECTION OUTPUT ;
    USE SIGNAL ;
    PORT
      LAYER metal10 ;
        RECT  1244.49 921.27 1245.29 922.07 ;
    END
  END rsp_data[17]
  PIN rsp_data[18]
    DIRECTION OUTPUT ;
    USE SIGNAL ;
    PORT
      LAYER metal10 ;
        RECT  1247.7 921.27 1248.5 922.07 ;
    END
  END rsp_data[18]
  PIN rsp_data[19]
    DIRECTION OUTPUT ;
    USE SIGNAL ;
    PORT
      LAYER metal10 ;
        RECT  1250.9 921.27 1251.7 922.07 ;
    END
  END rsp_data[19]
  PIN rsp_data[1]
    DIRECTION OUTPUT ;
    USE SIGNAL ;
    PORT
      LAYER metal10 ;
        RECT  1231.7 918.07 1232.5 918.87 ;
    END
  END rsp_data[1]
  PIN rsp_data[20]
    DIRECTION OUTPUT ;
    USE SIGNAL ;
    PORT
      LAYER metal10 ;
        RECT  1254.09 921.27 1254.89 922.07 ;
    END
  END rsp_data[20]
  PIN rsp_data[21]
    DIRECTION OUTPUT ;
    USE SIGNAL ;
    PORT
      LAYER metal10 ;
        RECT  1257.29 921.27 1258.09 922.07 ;
    END
  END rsp_data[21]
  PIN rsp_data[22]
    DIRECTION OUTPUT ;
    USE SIGNAL ;
    PORT
      LAYER metal10 ;
        RECT  1260.49 921.27 1261.29 922.07 ;
    END
  END rsp_data[22]
  PIN rsp_data[23]
    DIRECTION OUTPUT ;
    USE SIGNAL ;
    PORT
      LAYER metal10 ;
        RECT  1263.7 921.27 1264.5 922.07 ;
    END
  END rsp_data[23]
  PIN rsp_data[24]
    DIRECTION OUTPUT ;
    USE SIGNAL ;
    PORT
      LAYER metal10 ;
        RECT  1228.49 924.47 1229.29 925.27 ;
    END
  END rsp_data[24]
  PIN rsp_data[25]
    DIRECTION OUTPUT ;
    USE SIGNAL ;
    PORT
      LAYER metal10 ;
        RECT  1231.7 924.47 1232.5 925.27 ;
    END
  END rsp_data[25]
  PIN rsp_data[26]
    DIRECTION OUTPUT ;
    USE SIGNAL ;
    PORT
      LAYER metal10 ;
        RECT  1234.9 924.47 1235.7 925.27 ;
    END
  END rsp_data[26]
  PIN rsp_data[27]
    DIRECTION OUTPUT ;
    USE SIGNAL ;
    PORT
      LAYER metal10 ;
        RECT  1238.09 924.47 1238.89 925.27 ;
    END
  END rsp_data[27]
  PIN rsp_data[28]
    DIRECTION OUTPUT ;
    USE SIGNAL ;
    PORT
      LAYER metal10 ;
        RECT  1241.29 924.47 1242.09 925.27 ;
    END
  END rsp_data[28]
  PIN rsp_data[29]
    DIRECTION OUTPUT ;
    USE SIGNAL ;
    PORT
      LAYER metal10 ;
        RECT  1244.49 924.47 1245.29 925.27 ;
    END
  END rsp_data[29]
  PIN rsp_data[2]
    DIRECTION OUTPUT ;
    USE SIGNAL ;
    PORT
      LAYER metal10 ;
        RECT  1234.9 918.07 1235.7 918.87 ;
    END
  END rsp_data[2]
  PIN rsp_data[30]
    DIRECTION OUTPUT ;
    USE SIGNAL ;
    PORT
      LAYER metal10 ;
        RECT  1247.7 924.47 1248.5 925.27 ;
    END
  END rsp_data[30]
  PIN rsp_data[31]
    DIRECTION OUTPUT ;
    USE SIGNAL ;
    PORT
      LAYER metal10 ;
        RECT  1250.9 924.47 1251.7 925.27 ;
    END
  END rsp_data[31]
  PIN rsp_data[32]
    DIRECTION OUTPUT ;
    USE SIGNAL ;
    PORT
      LAYER metal10 ;
        RECT  1254.09 924.47 1254.89 925.27 ;
    END
  END rsp_data[32]
  PIN rsp_data[33]
    DIRECTION OUTPUT ;
    USE SIGNAL ;
    PORT
      LAYER metal10 ;
        RECT  1257.29 924.47 1258.09 925.27 ;
    END
  END rsp_data[33]
  PIN rsp_data[34]
    DIRECTION OUTPUT ;
    USE SIGNAL ;
    PORT
      LAYER metal10 ;
        RECT  1260.49 924.47 1261.29 925.27 ;
    END
  END rsp_data[34]
  PIN rsp_data[35]
    DIRECTION OUTPUT ;
    USE SIGNAL ;
    PORT
      LAYER metal10 ;
        RECT  1263.7 924.47 1264.5 925.27 ;
    END
  END rsp_data[35]
  PIN rsp_data[36]
    DIRECTION OUTPUT ;
    USE SIGNAL ;
    PORT
      LAYER metal10 ;
        RECT  1228.49 927.67 1229.29 928.47 ;
    END
  END rsp_data[36]
  PIN rsp_data[37]
    DIRECTION OUTPUT ;
    USE SIGNAL ;
    PORT
      LAYER metal10 ;
        RECT  1231.7 927.67 1232.5 928.47 ;
    END
  END rsp_data[37]
  PIN rsp_data[38]
    DIRECTION OUTPUT ;
    USE SIGNAL ;
    PORT
      LAYER metal10 ;
        RECT  1234.9 927.67 1235.7 928.47 ;
    END
  END rsp_data[38]
  PIN rsp_data[39]
    DIRECTION OUTPUT ;
    USE SIGNAL ;
    PORT
      LAYER metal10 ;
        RECT  1238.09 927.67 1238.89 928.47 ;
    END
  END rsp_data[39]
  PIN rsp_data[3]
    DIRECTION OUTPUT ;
    USE SIGNAL ;
    PORT
      LAYER metal10 ;
        RECT  1238.09 918.07 1238.89 918.87 ;
    END
  END rsp_data[3]
  PIN rsp_data[40]
    DIRECTION OUTPUT ;
    USE SIGNAL ;
    PORT
      LAYER metal10 ;
        RECT  1241.29 927.67 1242.09 928.47 ;
    END
  END rsp_data[40]
  PIN rsp_data[41]
    DIRECTION OUTPUT ;
    USE SIGNAL ;
    PORT
      LAYER metal10 ;
        RECT  1244.49 927.67 1245.29 928.47 ;
    END
  END rsp_data[41]
  PIN rsp_data[42]
    DIRECTION OUTPUT ;
    USE SIGNAL ;
    PORT
      LAYER metal10 ;
        RECT  1247.7 927.67 1248.5 928.47 ;
    END
  END rsp_data[42]
  PIN rsp_data[43]
    DIRECTION OUTPUT ;
    USE SIGNAL ;
    PORT
      LAYER metal10 ;
        RECT  1250.9 927.67 1251.7 928.47 ;
    END
  END rsp_data[43]
  PIN rsp_data[44]
    DIRECTION OUTPUT ;
    USE SIGNAL ;
    PORT
      LAYER metal10 ;
        RECT  1254.09 927.67 1254.89 928.47 ;
    END
  END rsp_data[44]
  PIN rsp_data[45]
    DIRECTION OUTPUT ;
    USE SIGNAL ;
    PORT
      LAYER metal10 ;
        RECT  1257.29 927.67 1258.09 928.47 ;
    END
  END rsp_data[45]
  PIN rsp_data[46]
    DIRECTION OUTPUT ;
    USE SIGNAL ;
    PORT
      LAYER metal10 ;
        RECT  1260.49 927.67 1261.29 928.47 ;
    END
  END rsp_data[46]
  PIN rsp_data[47]
    DIRECTION OUTPUT ;
    USE SIGNAL ;
    PORT
      LAYER metal10 ;
        RECT  1263.7 927.67 1264.5 928.47 ;
    END
  END rsp_data[47]
  PIN rsp_data[48]
    DIRECTION OUTPUT ;
    USE SIGNAL ;
    PORT
      LAYER metal10 ;
        RECT  1228.49 930.87 1229.29 931.67 ;
    END
  END rsp_data[48]
  PIN rsp_data[49]
    DIRECTION OUTPUT ;
    USE SIGNAL ;
    PORT
      LAYER metal10 ;
        RECT  1231.7 930.87 1232.5 931.67 ;
    END
  END rsp_data[49]
  PIN rsp_data[4]
    DIRECTION OUTPUT ;
    USE SIGNAL ;
    PORT
      LAYER metal10 ;
        RECT  1241.29 918.07 1242.09 918.87 ;
    END
  END rsp_data[4]
  PIN rsp_data[50]
    DIRECTION OUTPUT ;
    USE SIGNAL ;
    PORT
      LAYER metal10 ;
        RECT  1234.9 930.87 1235.7 931.67 ;
    END
  END rsp_data[50]
  PIN rsp_data[51]
    DIRECTION OUTPUT ;
    USE SIGNAL ;
    PORT
      LAYER metal10 ;
        RECT  1238.09 930.87 1238.89 931.67 ;
    END
  END rsp_data[51]
  PIN rsp_data[52]
    DIRECTION OUTPUT ;
    USE SIGNAL ;
    PORT
      LAYER metal10 ;
        RECT  1241.29 930.87 1242.09 931.67 ;
    END
  END rsp_data[52]
  PIN rsp_data[53]
    DIRECTION OUTPUT ;
    USE SIGNAL ;
    PORT
      LAYER metal10 ;
        RECT  1244.49 930.87 1245.29 931.67 ;
    END
  END rsp_data[53]
  PIN rsp_data[54]
    DIRECTION OUTPUT ;
    USE SIGNAL ;
    PORT
      LAYER metal10 ;
        RECT  1247.7 930.87 1248.5 931.67 ;
    END
  END rsp_data[54]
  PIN rsp_data[55]
    DIRECTION OUTPUT ;
    USE SIGNAL ;
    PORT
      LAYER metal10 ;
        RECT  1250.9 930.87 1251.7 931.67 ;
    END
  END rsp_data[55]
  PIN rsp_data[56]
    DIRECTION OUTPUT ;
    USE SIGNAL ;
    PORT
      LAYER metal10 ;
        RECT  1254.09 930.87 1254.89 931.67 ;
    END
  END rsp_data[56]
  PIN rsp_data[57]
    DIRECTION OUTPUT ;
    USE SIGNAL ;
    PORT
      LAYER metal10 ;
        RECT  1257.29 930.87 1258.09 931.67 ;
    END
  END rsp_data[57]
  PIN rsp_data[58]
    DIRECTION OUTPUT ;
    USE SIGNAL ;
    PORT
      LAYER metal10 ;
        RECT  1260.49 930.87 1261.29 931.67 ;
    END
  END rsp_data[58]
  PIN rsp_data[59]
    DIRECTION OUTPUT ;
    USE SIGNAL ;
    PORT
      LAYER metal10 ;
        RECT  1263.7 930.87 1264.5 931.67 ;
    END
  END rsp_data[59]
  PIN rsp_data[5]
    DIRECTION OUTPUT ;
    USE SIGNAL ;
    PORT
      LAYER metal10 ;
        RECT  1244.49 918.07 1245.29 918.87 ;
    END
  END rsp_data[5]
  PIN rsp_data[60]
    DIRECTION OUTPUT ;
    USE SIGNAL ;
    PORT
      LAYER metal10 ;
        RECT  1228.49 934.07 1229.29 934.87 ;
    END
  END rsp_data[60]
  PIN rsp_data[61]
    DIRECTION OUTPUT ;
    USE SIGNAL ;
    PORT
      LAYER metal10 ;
        RECT  1231.7 934.07 1232.5 934.87 ;
    END
  END rsp_data[61]
  PIN rsp_data[62]
    DIRECTION OUTPUT ;
    USE SIGNAL ;
    PORT
      LAYER metal10 ;
        RECT  1234.9 934.07 1235.7 934.87 ;
    END
  END rsp_data[62]
  PIN rsp_data[63]
    DIRECTION OUTPUT ;
    USE SIGNAL ;
    PORT
      LAYER metal10 ;
        RECT  1238.09 934.07 1238.89 934.87 ;
    END
  END rsp_data[63]
  PIN rsp_data[64]
    DIRECTION OUTPUT ;
    USE SIGNAL ;
    PORT
      LAYER metal10 ;
        RECT  1241.29 934.07 1242.09 934.87 ;
    END
  END rsp_data[64]
  PIN rsp_data[65]
    DIRECTION OUTPUT ;
    USE SIGNAL ;
    PORT
      LAYER metal10 ;
        RECT  1244.49 934.07 1245.29 934.87 ;
    END
  END rsp_data[65]
  PIN rsp_data[66]
    DIRECTION OUTPUT ;
    USE SIGNAL ;
    PORT
      LAYER metal10 ;
        RECT  1247.7 934.07 1248.5 934.87 ;
    END
  END rsp_data[66]
  PIN rsp_data[67]
    DIRECTION OUTPUT ;
    USE SIGNAL ;
    PORT
      LAYER metal10 ;
        RECT  1250.9 934.07 1251.7 934.87 ;
    END
  END rsp_data[67]
  PIN rsp_data[68]
    DIRECTION OUTPUT ;
    USE SIGNAL ;
    PORT
      LAYER metal10 ;
        RECT  1254.09 934.07 1254.89 934.87 ;
    END
  END rsp_data[68]
  PIN rsp_data[69]
    DIRECTION OUTPUT ;
    USE SIGNAL ;
    PORT
      LAYER metal10 ;
        RECT  1257.29 934.07 1258.09 934.87 ;
    END
  END rsp_data[69]
  PIN rsp_data[6]
    DIRECTION OUTPUT ;
    USE SIGNAL ;
    PORT
      LAYER metal10 ;
        RECT  1247.7 918.07 1248.5 918.87 ;
    END
  END rsp_data[6]
  PIN rsp_data[70]
    DIRECTION OUTPUT ;
    USE SIGNAL ;
    PORT
      LAYER metal10 ;
        RECT  1260.49 934.07 1261.29 934.87 ;
    END
  END rsp_data[70]
  PIN rsp_data[71]
    DIRECTION OUTPUT ;
    USE SIGNAL ;
    PORT
      LAYER metal10 ;
        RECT  1263.7 934.07 1264.5 934.87 ;
    END
  END rsp_data[71]
  PIN rsp_data[72]
    DIRECTION OUTPUT ;
    USE SIGNAL ;
    PORT
      LAYER metal10 ;
        RECT  1228.49 937.27 1229.29 938.07 ;
    END
  END rsp_data[72]
  PIN rsp_data[73]
    DIRECTION OUTPUT ;
    USE SIGNAL ;
    PORT
      LAYER metal10 ;
        RECT  1231.7 937.27 1232.5 938.07 ;
    END
  END rsp_data[73]
  PIN rsp_data[74]
    DIRECTION OUTPUT ;
    USE SIGNAL ;
    PORT
      LAYER metal10 ;
        RECT  1234.9 937.27 1235.7 938.07 ;
    END
  END rsp_data[74]
  PIN rsp_data[75]
    DIRECTION OUTPUT ;
    USE SIGNAL ;
    PORT
      LAYER metal10 ;
        RECT  1238.09 937.27 1238.89 938.07 ;
    END
  END rsp_data[75]
  PIN rsp_data[76]
    DIRECTION OUTPUT ;
    USE SIGNAL ;
    PORT
      LAYER metal10 ;
        RECT  1241.29 937.27 1242.09 938.07 ;
    END
  END rsp_data[76]
  PIN rsp_data[77]
    DIRECTION OUTPUT ;
    USE SIGNAL ;
    PORT
      LAYER metal10 ;
        RECT  1244.49 937.27 1245.29 938.07 ;
    END
  END rsp_data[77]
  PIN rsp_data[78]
    DIRECTION OUTPUT ;
    USE SIGNAL ;
    PORT
      LAYER metal10 ;
        RECT  1247.7 937.27 1248.5 938.07 ;
    END
  END rsp_data[78]
  PIN rsp_data[79]
    DIRECTION OUTPUT ;
    USE SIGNAL ;
    PORT
      LAYER metal10 ;
        RECT  1250.9 937.27 1251.7 938.07 ;
    END
  END rsp_data[79]
  PIN rsp_data[7]
    DIRECTION OUTPUT ;
    USE SIGNAL ;
    PORT
      LAYER metal10 ;
        RECT  1250.9 918.07 1251.7 918.87 ;
    END
  END rsp_data[7]
  PIN rsp_data[80]
    DIRECTION OUTPUT ;
    USE SIGNAL ;
    PORT
      LAYER metal10 ;
        RECT  1254.09 937.27 1254.89 938.07 ;
    END
  END rsp_data[80]
  PIN rsp_data[81]
    DIRECTION OUTPUT ;
    USE SIGNAL ;
    PORT
      LAYER metal10 ;
        RECT  1257.29 937.27 1258.09 938.07 ;
    END
  END rsp_data[81]
  PIN rsp_data[82]
    DIRECTION OUTPUT ;
    USE SIGNAL ;
    PORT
      LAYER metal10 ;
        RECT  1260.49 937.27 1261.29 938.07 ;
    END
  END rsp_data[82]
  PIN rsp_data[83]
    DIRECTION OUTPUT ;
    USE SIGNAL ;
    PORT
      LAYER metal10 ;
        RECT  1263.7 937.27 1264.5 938.07 ;
    END
  END rsp_data[83]
  PIN rsp_data[84]
    DIRECTION OUTPUT ;
    USE SIGNAL ;
    PORT
      LAYER metal10 ;
        RECT  1228.49 940.47 1229.29 941.27 ;
    END
  END rsp_data[84]
  PIN rsp_data[85]
    DIRECTION OUTPUT ;
    USE SIGNAL ;
    PORT
      LAYER metal10 ;
        RECT  1231.7 940.47 1232.5 941.27 ;
    END
  END rsp_data[85]
  PIN rsp_data[86]
    DIRECTION OUTPUT ;
    USE SIGNAL ;
    PORT
      LAYER metal10 ;
        RECT  1234.9 940.47 1235.7 941.27 ;
    END
  END rsp_data[86]
  PIN rsp_data[87]
    DIRECTION OUTPUT ;
    USE SIGNAL ;
    PORT
      LAYER metal10 ;
        RECT  1238.09 940.47 1238.89 941.27 ;
    END
  END rsp_data[87]
  PIN rsp_data[88]
    DIRECTION OUTPUT ;
    USE SIGNAL ;
    PORT
      LAYER metal10 ;
        RECT  1241.29 940.47 1242.09 941.27 ;
    END
  END rsp_data[88]
  PIN rsp_data[89]
    DIRECTION OUTPUT ;
    USE SIGNAL ;
    PORT
      LAYER metal10 ;
        RECT  1244.49 940.47 1245.29 941.27 ;
    END
  END rsp_data[89]
  PIN rsp_data[8]
    DIRECTION OUTPUT ;
    USE SIGNAL ;
    PORT
      LAYER metal10 ;
        RECT  1254.09 918.07 1254.89 918.87 ;
    END
  END rsp_data[8]
  PIN rsp_data[90]
    DIRECTION OUTPUT ;
    USE SIGNAL ;
    PORT
      LAYER metal10 ;
        RECT  1247.7 940.47 1248.5 941.27 ;
    END
  END rsp_data[90]
  PIN rsp_data[91]
    DIRECTION OUTPUT ;
    USE SIGNAL ;
    PORT
      LAYER metal10 ;
        RECT  1250.9 940.47 1251.7 941.27 ;
    END
  END rsp_data[91]
  PIN rsp_data[92]
    DIRECTION OUTPUT ;
    USE SIGNAL ;
    PORT
      LAYER metal10 ;
        RECT  1254.09 940.47 1254.89 941.27 ;
    END
  END rsp_data[92]
  PIN rsp_data[93]
    DIRECTION OUTPUT ;
    USE SIGNAL ;
    PORT
      LAYER metal10 ;
        RECT  1257.29 940.47 1258.09 941.27 ;
    END
  END rsp_data[93]
  PIN rsp_data[94]
    DIRECTION OUTPUT ;
    USE SIGNAL ;
    PORT
      LAYER metal10 ;
        RECT  1260.49 940.47 1261.29 941.27 ;
    END
  END rsp_data[94]
  PIN rsp_data[95]
    DIRECTION OUTPUT ;
    USE SIGNAL ;
    PORT
      LAYER metal10 ;
        RECT  1263.7 940.47 1264.5 941.27 ;
    END
  END rsp_data[95]
  PIN rsp_data[96]
    DIRECTION OUTPUT ;
    USE SIGNAL ;
    PORT
      LAYER metal10 ;
        RECT  1228.49 943.67 1229.29 944.47 ;
    END
  END rsp_data[96]
  PIN rsp_data[97]
    DIRECTION OUTPUT ;
    USE SIGNAL ;
    PORT
      LAYER metal10 ;
        RECT  1231.7 943.67 1232.5 944.47 ;
    END
  END rsp_data[97]
  PIN rsp_data[98]
    DIRECTION OUTPUT ;
    USE SIGNAL ;
    PORT
      LAYER metal10 ;
        RECT  1234.9 943.67 1235.7 944.47 ;
    END
  END rsp_data[98]
  PIN rsp_data[99]
    DIRECTION OUTPUT ;
    USE SIGNAL ;
    PORT
      LAYER metal10 ;
        RECT  1238.09 943.67 1238.89 944.47 ;
    END
  END rsp_data[99]
  PIN rsp_data[9]
    DIRECTION OUTPUT ;
    USE SIGNAL ;
    PORT
      LAYER metal10 ;
        RECT  1257.29 918.07 1258.09 918.87 ;
    END
  END rsp_data[9]
  PIN rsp_error
    DIRECTION OUTPUT ;
    USE SIGNAL ;
    PORT
      LAYER metal10 ;
        RECT  1.295 81.27 2.095 82.07 ;
    END
  END rsp_error
  PIN rsp_ready
    DIRECTION INPUT ;
    USE SIGNAL ;
    PORT
      LAYER metal10 ;
        RECT  1.295 84.47 2.095 85.27 ;
    END
  END rsp_ready
  PIN rsp_valid
    DIRECTION OUTPUT ;
    USE SIGNAL ;
    PORT
      LAYER metal10 ;
        RECT  1.295 87.67 2.095 88.47 ;
    END
  END rsp_valid
  PIN VDD
    DIRECTION INOUT ;
    USE POWER ;
    PORT
      LAYER metal7 ;
        RECT  20.14 1837.3 1849.84 1838.7 ;
        RECT  20.14 1807.3 1849.84 1808.7 ;
        RECT  20.14 1777.3 1849.84 1778.7 ;
        RECT  20.14 1747.3 1849.84 1748.7 ;
        RECT  20.14 1717.3 1849.84 1718.7 ;
        RECT  20.14 1687.3 1849.84 1688.7 ;
        RECT  20.14 1657.3 1849.84 1658.7 ;
        RECT  20.14 1627.3 1849.84 1628.7 ;
        RECT  20.14 1597.3 1849.84 1598.7 ;
        RECT  20.14 1567.3 1849.84 1568.7 ;
        RECT  20.14 1537.3 1849.84 1538.7 ;
        RECT  20.14 1507.3 1849.84 1508.7 ;
        RECT  20.14 1477.3 1849.84 1478.7 ;
        RECT  20.14 1447.3 1849.84 1448.7 ;
        RECT  20.14 1417.3 1849.84 1418.7 ;
        RECT  20.14 1387.3 1849.84 1388.7 ;
        RECT  20.14 1357.3 1849.84 1358.7 ;
        RECT  20.14 1327.3 1849.84 1328.7 ;
        RECT  20.14 1297.3 1849.84 1298.7 ;
        RECT  20.14 1267.3 1849.84 1268.7 ;
        RECT  20.14 1237.3 1849.84 1238.7 ;
        RECT  20.14 1207.3 1849.84 1208.7 ;
        RECT  20.14 1177.3 1849.84 1178.7 ;
        RECT  20.14 1147.3 1849.84 1148.7 ;
        RECT  20.14 1117.3 1849.84 1118.7 ;
        RECT  20.14 1087.3 1849.84 1088.7 ;
        RECT  20.14 1057.3 1849.84 1058.7 ;
        RECT  20.14 1027.3 1849.84 1028.7 ;
        RECT  20.14 997.3 1849.84 998.7 ;
        RECT  20.14 967.3 1849.84 968.7 ;
        RECT  20.14 937.3 1849.84 938.7 ;
        RECT  20.14 907.3 1849.84 908.7 ;
        RECT  20.14 877.3 1849.84 878.7 ;
        RECT  20.14 847.3 1849.84 848.7 ;
        RECT  20.14 817.3 1849.84 818.7 ;
        RECT  20.14 787.3 1849.84 788.7 ;
        RECT  20.14 757.3 1849.84 758.7 ;
        RECT  20.14 727.3 1849.84 728.7 ;
        RECT  20.14 697.3 1849.84 698.7 ;
        RECT  20.14 667.3 1849.84 668.7 ;
        RECT  20.14 637.3 1849.84 638.7 ;
        RECT  20.14 607.3 1849.84 608.7 ;
        RECT  20.14 577.3 1849.84 578.7 ;
        RECT  20.14 547.3 1849.84 548.7 ;
        RECT  20.14 517.3 1849.84 518.7 ;
        RECT  20.14 487.3 1849.84 488.7 ;
        RECT  20.14 457.3 1849.84 458.7 ;
        RECT  20.14 427.3 1849.84 428.7 ;
        RECT  20.14 397.3 1849.84 398.7 ;
        RECT  20.14 367.3 1849.84 368.7 ;
        RECT  20.14 337.3 1849.84 338.7 ;
        RECT  20.14 307.3 1849.84 308.7 ;
        RECT  20.14 277.3 1849.84 278.7 ;
        RECT  20.14 247.3 1849.84 248.7 ;
        RECT  20.14 217.3 1849.84 218.7 ;
        RECT  20.14 187.3 1849.84 188.7 ;
        RECT  20.14 157.3 1849.84 158.7 ;
        RECT  20.14 127.3 1849.84 128.7 ;
        RECT  20.14 97.3 1849.84 98.7 ;
        RECT  20.14 67.3 1849.84 68.7 ;
        RECT  20.14 37.3 1849.84 38.7 ;
    END
  END VDD
  PIN VSS
    DIRECTION INOUT ;
    USE GROUND ;
    PORT
      LAYER metal7 ;
        RECT  20.14 1822.3 1849.84 1823.7 ;
        RECT  20.14 1792.3 1849.84 1793.7 ;
        RECT  20.14 1762.3 1849.84 1763.7 ;
        RECT  20.14 1732.3 1849.84 1733.7 ;
        RECT  20.14 1702.3 1849.84 1703.7 ;
        RECT  20.14 1672.3 1849.84 1673.7 ;
        RECT  20.14 1642.3 1849.84 1643.7 ;
        RECT  20.14 1612.3 1849.84 1613.7 ;
        RECT  20.14 1582.3 1849.84 1583.7 ;
        RECT  20.14 1552.3 1849.84 1553.7 ;
        RECT  20.14 1522.3 1849.84 1523.7 ;
        RECT  20.14 1492.3 1849.84 1493.7 ;
        RECT  20.14 1462.3 1849.84 1463.7 ;
        RECT  20.14 1432.3 1849.84 1433.7 ;
        RECT  20.14 1402.3 1849.84 1403.7 ;
        RECT  20.14 1372.3 1849.84 1373.7 ;
        RECT  20.14 1342.3 1849.84 1343.7 ;
        RECT  20.14 1312.3 1849.84 1313.7 ;
        RECT  20.14 1282.3 1849.84 1283.7 ;
        RECT  20.14 1252.3 1849.84 1253.7 ;
        RECT  20.14 1222.3 1849.84 1223.7 ;
        RECT  20.14 1192.3 1849.84 1193.7 ;
        RECT  20.14 1162.3 1849.84 1163.7 ;
        RECT  20.14 1132.3 1849.84 1133.7 ;
        RECT  20.14 1102.3 1849.84 1103.7 ;
        RECT  20.14 1072.3 1849.84 1073.7 ;
        RECT  20.14 1042.3 1849.84 1043.7 ;
        RECT  20.14 1012.3 1849.84 1013.7 ;
        RECT  20.14 982.3 1849.84 983.7 ;
        RECT  20.14 952.3 1849.84 953.7 ;
        RECT  20.14 922.3 1849.84 923.7 ;
        RECT  20.14 892.3 1849.84 893.7 ;
        RECT  20.14 862.3 1849.84 863.7 ;
        RECT  20.14 832.3 1849.84 833.7 ;
        RECT  20.14 802.3 1849.84 803.7 ;
        RECT  20.14 772.3 1849.84 773.7 ;
        RECT  20.14 742.3 1849.84 743.7 ;
        RECT  20.14 712.3 1849.84 713.7 ;
        RECT  20.14 682.3 1849.84 683.7 ;
        RECT  20.14 652.3 1849.84 653.7 ;
        RECT  20.14 622.3 1849.84 623.7 ;
        RECT  20.14 592.3 1849.84 593.7 ;
        RECT  20.14 562.3 1849.84 563.7 ;
        RECT  20.14 532.3 1849.84 533.7 ;
        RECT  20.14 502.3 1849.84 503.7 ;
        RECT  20.14 472.3 1849.84 473.7 ;
        RECT  20.14 442.3 1849.84 443.7 ;
        RECT  20.14 412.3 1849.84 413.7 ;
        RECT  20.14 382.3 1849.84 383.7 ;
        RECT  20.14 352.3 1849.84 353.7 ;
        RECT  20.14 322.3 1849.84 323.7 ;
        RECT  20.14 292.3 1849.84 293.7 ;
        RECT  20.14 262.3 1849.84 263.7 ;
        RECT  20.14 232.3 1849.84 233.7 ;
        RECT  20.14 202.3 1849.84 203.7 ;
        RECT  20.14 172.3 1849.84 173.7 ;
        RECT  20.14 142.3 1849.84 143.7 ;
        RECT  20.14 112.3 1849.84 113.7 ;
        RECT  20.14 82.3 1849.84 83.7 ;
        RECT  20.14 52.3 1849.84 53.7 ;
        RECT  20.14 22.3 1849.84 23.7 ;
    END
  END VSS
  OBS
    LAYER metal1 ;
     RECT  0.495 18.87 1849.84 1849.82 ;
    LAYER metal2 ;
     RECT  0.495 18.87 1849.84 1849.82 ;
    LAYER metal3 ;
     RECT  0.495 18.87 1849.84 1849.82 ;
    LAYER metal4 ;
     RECT  0.495 18.87 1849.84 1849.82 ;
    LAYER metal5 ;
     RECT  0.495 18.87 1849.84 1849.82 ;
    LAYER metal6 ;
     RECT  0.495 18.87 1849.84 1849.82 ;
    LAYER metal7 ;
     RECT  0.495 18.87 1849.84 1849.82 ;
    LAYER metal8 ;
     RECT  0.495 18.87 1849.84 1849.82 ;
    LAYER metal9 ;
     RECT  0.495 18.87 1849.84 1849.82 ;
    LAYER metal10 ;
     RECT  0.495 18.87 1849.84 1849.82 ;
  END
END block_v1_r
END LIBRARY
